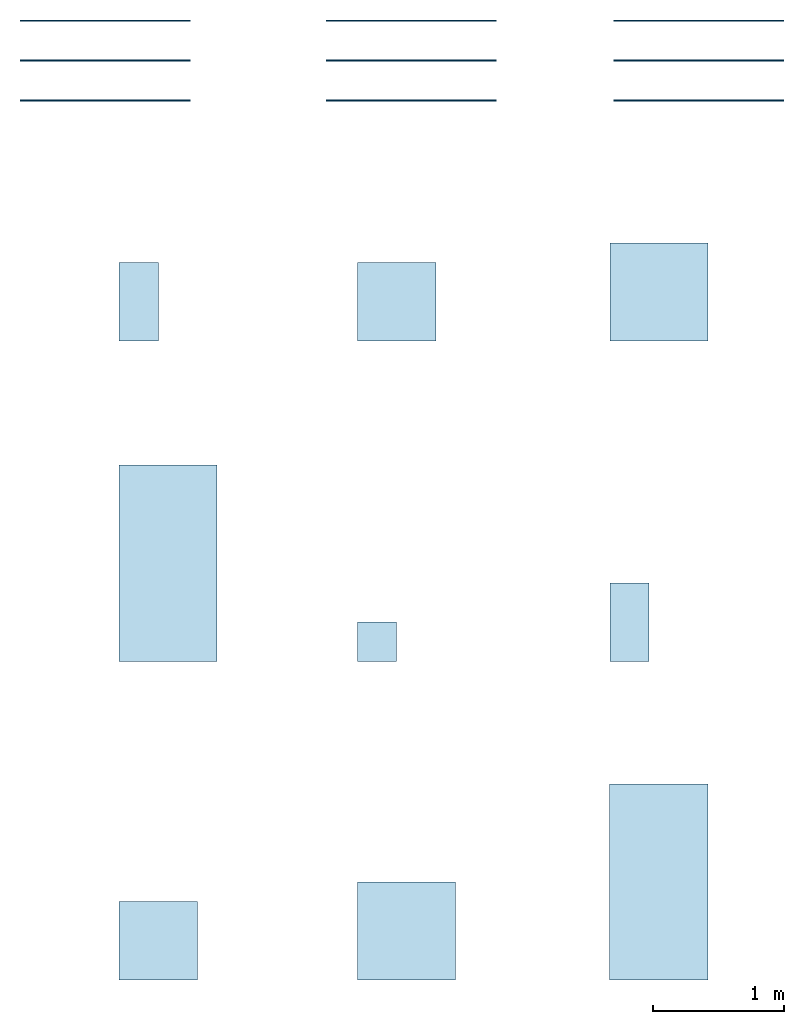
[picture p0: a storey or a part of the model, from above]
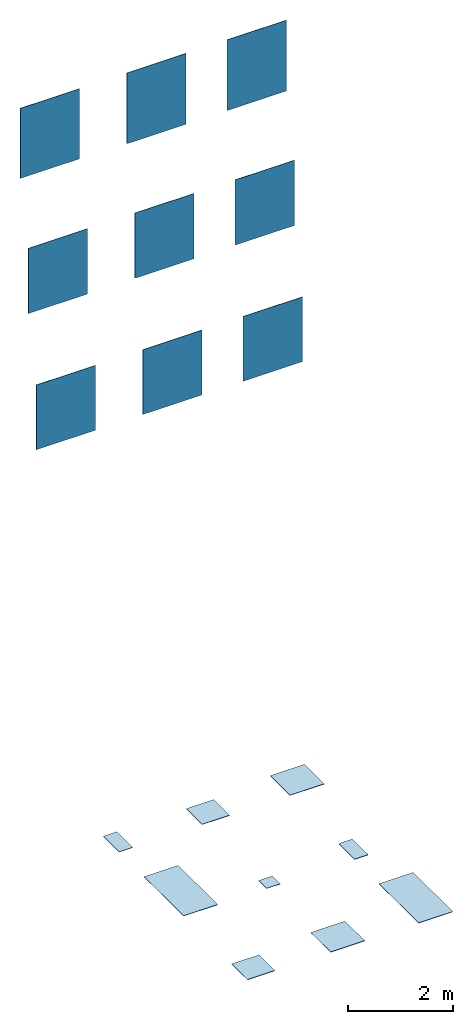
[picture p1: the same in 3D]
Properties of the parts of a building model (IFC2X3)

# File
Description: ViewDefinition [CoordinationView_V2.0]
File name: Project Number
Time: 2021-09-16T11:54:57
Written by: The EXPRESS Data Manager Version 5.02.0100.07 : 28 Aug 2013
Made in: 20190808_0900(x64) - Exporter 19.5.0.0 - Alternate UI 19.5.0.0
Comment: STEP Physical File produced by: The EXPRESS Data Manager Version 5.02.0100.07 : 28 Aug 2013 * Module: EDMstepFileFactory/EDMstandAlone * Creation date: Thu Sep 16 11:54:57 2021 * Host: Davide1988 * Database: C:\Users\DAVIDE~1\AppData\Local\Temp\{4796FC2B-F4B8-4F15-B6A7-0CD5D685FC9C}\ifc * Database version: 5507 * Database creation date: Thu Sep 16 11:54:56 2021 * Schema: IFC2X3 * Model: DataRepository.ifc * Model creation date: Thu Sep 16 11:54:56 2021 * Header model: DataRepository.ifc_HeaderModel * Header model creation date: Thu Sep 16 11:54:56 2021 * EDMuser: sdai-user * EDMgroup: sdai-group * License ID and type: 5605 : Permanent license. Expiry date: * EDMstepFileFactory options: 020000

# IfcProject, Project Number
LongName: Refin-Blended; Phase: Project Status

# IfcSite, Default
RefLatitude: 51, 30, 0, 549316; RefLongitude: 0, -7, -34, -450321; RefElevation: 0 mm
Pset_ProductRequirements - Category: Project Information

# IfcBuilding
Pset_BuildingCommon - NumberOfStoreys: 1
Pset_ProductRequirements - Category: Project Information

# IfcBuildingStorey: Level:Circle Head - Project Datum, Level 0
LongName: Level 0; Elevation: 0 mm
Pset_AirSideSystemInformation - Name: Level 0
Pset_ProductRequirements - Name: Level 0; Category: Levels

# IfcSlab: Floor:Floor_Tiles_Refin-Prestigio_Onyx-Grey-30x30 NZ92, Floor:Floor_Tiles_Refin-Prestigio_Onyx-Grey-30x30 NZ92:304948
In: Level 0
Type - PredefinedType: FLOOR; Material: Prestigio Onyx-Grey-30x30 NZ92 9 mm, <Unnamed> 1 mm
Type - Pset_ConcreteElementGeneral - FireRating: INERT
Type - Pset_ElementShading - Roughness: 914.4 mm; Color: LIGHT-GREY
Type - Pset_FireRatingProperties - SurfaceSpreadOfFlame: INERT
Type - Pset_ManufacturerOccurrence - BarCode: N/A; SerialNumber: N/A
Type - Pset_ManufacturerTypeInformation - ArticleNumber: NZ92; ModelReference: NZ92; ModelLabel: GREY MOSAICO T LUCIDO R 30X30; Manufacturer: info@refin.it; ProductionYear: N/A
Type - Pset_PrecastConcreteElementGeneral - SerialNumber: N/A
Type - Pset_ProductRequirements - Name: Prestigio Onyx_Grey_Mosaico_T_Lucido_30X30 R; Category: Pr_35_93_96_19:Ceramic tiles
Type - Pset_QuantityTakeOff - Reference: N/A
Type - Pset_ReinforcementBarPitchOfSlab - Description: PORCELAIN STONEWARE TILE; Reference: N/A
Type - Pset_SlabCommon - Reference: N/A; IsExternal: no; AcousticRating: N/A; FireRating: INERT; SurfaceSpreadOfFlame: INERT
Type - Pset_Warranty - WarrantyContent: N/A; Exclusions: N/A
Pset_ProductRequirements - Category: Floors
Pset_SlabCommon - LoadBearing: no; PitchAngle: 0 deg

# IfcSlab: Floor:Floor_Tiles_Refin-Prestigio_Onyx-Grey-30x60 NW02, Floor:Floor_Tiles_Refin-Prestigio_Onyx-Grey-30x60 NW02:304668
In: Level 0
Type - PredefinedType: FLOOR; Material: Prestigio Onyx-Grey-30x60 NW02 9 mm, <Unnamed> 1 mm
Type - Pset_ConcreteElementGeneral - FireRating: INERT
Type - Pset_ElementShading - Roughness: 914.4 mm; Color: LIGHT-GREY
Type - Pset_FireRatingProperties - SurfaceSpreadOfFlame: INERT
Type - Pset_ManufacturerOccurrence - BarCode: N/A; SerialNumber: N/A
Type - Pset_ManufacturerTypeInformation - ArticleNumber: NW02; ModelReference: NW02; ModelLabel: GREY LUCIDO R 30X60; Manufacturer: info@refin.it; ProductionYear: N/A
Type - Pset_PrecastConcreteElementGeneral - SerialNumber: N/A
Type - Pset_ProductRequirements - Name: Prestigio Onyx_Grey_Lucido_30X60 R; Category: Pr_35_93_96_19:Ceramic tiles
Type - Pset_QuantityTakeOff - Reference: N/A
Type - Pset_ReinforcementBarPitchOfSlab - Description: PORCELAIN STONEWARE TILE; Reference: N/A
Type - Pset_SlabCommon - Reference: N/A; IsExternal: no; AcousticRating: N/A; FireRating: INERT; SurfaceSpreadOfFlame: INERT
Type - Pset_Warranty - WarrantyContent: N/A; Exclusions: N/A
Pset_ProductRequirements - Category: Floors
Pset_SlabCommon - LoadBearing: no; PitchAngle: 0 deg

# IfcSlab: Floor:Floor_Tiles_Refin-Prestigio_Onyx-Grey-60x60 NZ96, Floor:Floor_Tiles_Refin-Prestigio_Onyx-Grey-60x60 NZ96:324498
In: Level 0
Type - PredefinedType: FLOOR; Material: Prestigio Onyx-Grey-60x60 NZ96 9 mm, <Unnamed> 1 mm
Type - Pset_ConcreteElementGeneral - FireRating: INERT
Type - Pset_ElementShading - Roughness: 914.4 mm; Color: LIGHT-GREY
Type - Pset_FireRatingProperties - SurfaceSpreadOfFlame: INERT
Type - Pset_ManufacturerOccurrence - BarCode: N/A; SerialNumber: N/A
Type - Pset_ManufacturerTypeInformation - ArticleNumber: NZ96; ModelReference: NZ96; ModelLabel: GREY LUCIDO R 60X60; Manufacturer: info@refin.it; ProductionYear: N/A
Type - Pset_PrecastConcreteElementGeneral - SerialNumber: N/A
Type - Pset_ProductRequirements - Name: Prestigio Onyx_Grey_Lucido_60X60 R; Category: Pr_35_93_96_19:Ceramic tiles
Type - Pset_QuantityTakeOff - Reference: N/A
Type - Pset_ReinforcementBarPitchOfSlab - Description: PORCELAIN STONEWARE TILE; Reference: N/A
Type - Pset_SlabCommon - Reference: N/A; IsExternal: no; AcousticRating: N/A; FireRating: INERT; SurfaceSpreadOfFlame: INERT
Type - Pset_Warranty - WarrantyContent: N/A; Exclusions: N/A
Pset_ProductRequirements - Category: Floors
Pset_SlabCommon - LoadBearing: no; PitchAngle: 0 deg

# IfcSlab: Floor:Floor_Tiles_Refin-Prestigio_Onyx-Grey-75x150 NV70, Floor:Floor_Tiles_Refin-Prestigio_Onyx-Grey-75x150 NV70:304956
In: Level 0
Type - PredefinedType: FLOOR; Material: Prestigio Onyx-Grey-75x150 NV70 9 mm, <Unnamed> 1 mm
Type - Pset_ConcreteElementGeneral - FireRating: INERT
Type - Pset_ElementShading - Roughness: 914.4 mm; Color: LIGHT-GREY
Type - Pset_FireRatingProperties - SurfaceSpreadOfFlame: INERT
Type - Pset_ManufacturerOccurrence - BarCode: N/A; SerialNumber: N/A
Type - Pset_ManufacturerTypeInformation - ArticleNumber: NV70; ModelReference: NV70; ModelLabel: GREY LUCIDO R 75X150; Manufacturer: info@refin.it; ProductionYear: N/A
Type - Pset_PrecastConcreteElementGeneral - SerialNumber: N/A
Type - Pset_ProductRequirements - Name: Prestigio Onyx_Grey_Lucido_75X150 R; Category: Pr_35_93_96_19:Ceramic tiles
Type - Pset_QuantityTakeOff - Reference: N/A
Type - Pset_ReinforcementBarPitchOfSlab - Description: PORCELAIN STONEWARE TILE; Reference: N/A
Type - Pset_SlabCommon - Reference: N/A; IsExternal: no; AcousticRating: N/A; FireRating: INERT; SurfaceSpreadOfFlame: INERT
Type - Pset_Warranty - WarrantyContent: N/A; Exclusions: N/A
Pset_ProductRequirements - Category: Floors
Pset_SlabCommon - LoadBearing: no; PitchAngle: 0 deg

# IfcSlab: Floor:Floor_Tiles_Refin-Prestigio_Onyx-Grey-75x75 NZ82, Floor:Floor_Tiles_Refin-Prestigio_Onyx-Grey-75x75 NZ82:285295
In: Level 0
Type - PredefinedType: FLOOR; Material: Prestigio Onyx-Grey-75x75 NZ82 9 mm, <Unnamed> 1 mm
Type - Pset_ConcreteElementGeneral - FireRating: INERT
Type - Pset_ElementShading - Roughness: 914.4 mm; Color: LIGHT-GREY
Type - Pset_FireRatingProperties - SurfaceSpreadOfFlame: INERT
Type - Pset_ManufacturerOccurrence - BarCode: N/A; SerialNumber: N/A
Type - Pset_ManufacturerTypeInformation - ArticleNumber: NZ82; ModelReference: NZ82; ModelLabel: GREY LUCIDO R 75X75; Manufacturer: info@refin.it; ProductionYear: N/A
Type - Pset_PrecastConcreteElementGeneral - SerialNumber: N/A
Type - Pset_ProductRequirements - Name: Prestigio_Onyx_Grey_Lucido_75X75 R; Category: Pr_35_93_96_19:Ceramic tiles
Type - Pset_QuantityTakeOff - Reference: N/A
Type - Pset_ReinforcementBarPitchOfSlab - Description: PORCELAIN STONEWARE TILE; Reference: N/A
Type - Pset_SlabCommon - Reference: N/A; IsExternal: no; AcousticRating: N/A; FireRating: INERT; SurfaceSpreadOfFlame: INERT
Type - Pset_Warranty - WarrantyContent: N/A; Exclusions: N/A
Pset_ProductRequirements - Category: Floors
Pset_SlabCommon - LoadBearing: no; PitchAngle: 0 deg

# IfcSlab: Floor:Floor_Tiles_Refin-Prestigio_Onyx-Grey_Soft-30x60 NW05, Floor:Floor_Tiles_Refin-Prestigio_Onyx-Grey_Soft-30x60 NW05:304932
In: Level 0
Type - PredefinedType: FLOOR; Material: Prestigio Onyx-Grey-Soft-30x60 NW05 9 mm, <Unnamed> 1 mm
Type - Pset_ConcreteElementGeneral - FireRating: INERT
Type - Pset_ElementShading - Roughness: 914.4 mm; Color: LIGHT-GREY
Type - Pset_FireRatingProperties - SurfaceSpreadOfFlame: INERT
Type - Pset_ManufacturerOccurrence - BarCode: N/A; SerialNumber: N/A
Type - Pset_ManufacturerTypeInformation - ArticleNumber: NW05; ModelReference: NW05; ModelLabel: GREY SOFT R 30X60; Manufacturer: info@refin.it; ProductionYear: N/A
Type - Pset_PrecastConcreteElementGeneral - SerialNumber: N/A
Type - Pset_ProductRequirements - Name: Prestigio Onyx_Grey_Soft_30X60 R; Category: Pr_35_93_96_19:Ceramic tiles
Type - Pset_QuantityTakeOff - Reference: N/A
Type - Pset_ReinforcementBarPitchOfSlab - Description: PORCELAIN STONEWARE TILE; Reference: N/A
Type - Pset_SlabCommon - Reference: N/A; IsExternal: no; AcousticRating: N/A; FireRating: INERT; SurfaceSpreadOfFlame: INERT
Type - Pset_Warranty - WarrantyContent: N/A; Exclusions: N/A
Pset_ProductRequirements - Category: Floors
Pset_SlabCommon - LoadBearing: no; PitchAngle: 0 deg

# IfcSlab: Floor:Floor_Tiles_Refin-Prestigio_Onyx-Grey_Soft-60x60 NZ99, Floor:Floor_Tiles_Refin-Prestigio_Onyx-Grey_Soft-60x60 NZ99:305509
In: Level 0
Type - PredefinedType: FLOOR; Material: Prestigio Onyx-Grey-Soft-60x60 NZ99 9 mm, <Unnamed> 1 mm
Type - Pset_ConcreteElementGeneral - FireRating: INERT
Type - Pset_ElementShading - Roughness: 914.4 mm; Color: LIGHT-GREY
Type - Pset_FireRatingProperties - SurfaceSpreadOfFlame: INERT
Type - Pset_ManufacturerOccurrence - BarCode: N/A; SerialNumber: N/A
Type - Pset_ManufacturerTypeInformation - ArticleNumber: NZ99; ModelReference: NZ99; ModelLabel: GREY SOFT R 60X60; Manufacturer: info@refin.it; ProductionYear: N/A
Type - Pset_PrecastConcreteElementGeneral - SerialNumber: N/A
Type - Pset_ProductRequirements - Name: Prestigio Onyx_Grey_Soft_60X60 R; Category: Pr_35_93_96_19:Ceramic tiles
Type - Pset_QuantityTakeOff - Reference: N/A
Type - Pset_ReinforcementBarPitchOfSlab - Description: PORCELAIN STONEWARE TILE; Reference: N/A
Type - Pset_SlabCommon - Reference: N/A; IsExternal: no; AcousticRating: N/A; FireRating: INERT; SurfaceSpreadOfFlame: INERT
Type - Pset_Warranty - WarrantyContent: N/A; Exclusions: N/A
Pset_ProductRequirements - Category: Floors
Pset_SlabCommon - LoadBearing: no; PitchAngle: 0 deg

# IfcSlab: Floor:Floor_Tiles_Refin-Prestigio_Onyx-Grey_Soft-75x150 NZ79, Floor:Floor_Tiles_Refin-Prestigio_Onyx-Grey_Soft-75x150 NZ79:339650
In: Level 0
Type - PredefinedType: FLOOR; Material: Prestigio Onyx-Grey-Soft-75x150 NZ79 9 mm, <Unnamed> 1 mm
Type - Pset_ConcreteElementGeneral - FireRating: INERT
Type - Pset_ElementShading - Roughness: 914.4 mm; Color: LIGHT-GREY
Type - Pset_FireRatingProperties - SurfaceSpreadOfFlame: INERT
Type - Pset_ManufacturerOccurrence - BarCode: N/A; SerialNumber: N/A
Type - Pset_ManufacturerTypeInformation - ArticleNumber: NZ79; ModelReference: NZ79; ModelLabel: GREY SOFT R 75X150; Manufacturer: info@refin.it; ProductionYear: N/A
Type - Pset_PrecastConcreteElementGeneral - SerialNumber: N/A
Type - Pset_ProductRequirements - Name: Prestigio Onyx_Grey_Soft_75X150 R; Category: Pr_35_93_96_19:Ceramic tiles
Type - Pset_QuantityTakeOff - Reference: N/A
Type - Pset_ReinforcementBarPitchOfSlab - Description: PORCELAIN STONEWARE TILE; Reference: N/A
Type - Pset_SlabCommon - Reference: N/A; IsExternal: no; AcousticRating: N/A; FireRating: INERT; SurfaceSpreadOfFlame: INERT
Type - Pset_Warranty - WarrantyContent: N/A; Exclusions: N/A
Pset_ProductRequirements - Category: Floors
Pset_SlabCommon - LoadBearing: no; PitchAngle: 0 deg

# IfcSlab: Floor:Floor_Tiles_Refin-Prestigio_Onyx-Grey_Soft-75x75 NZ85, Floor:Floor_Tiles_Refin-Prestigio_Onyx-Grey_Soft-75x75 NZ85:339635
In: Level 0
Type - PredefinedType: FLOOR; Material: Prestigio Onyx-Grey-Soft-75x75 NZ85 9 mm, <Unnamed> 1 mm
Type - Pset_ConcreteElementGeneral - FireRating: INERT
Type - Pset_ElementShading - Roughness: 914.4 mm; Color: LIGHT-GREY
Type - Pset_FireRatingProperties - SurfaceSpreadOfFlame: INERT
Type - Pset_ManufacturerOccurrence - BarCode: N/A; SerialNumber: N/A
Type - Pset_ManufacturerTypeInformation - ArticleNumber: NZ85; ModelReference: NZ85; ModelLabel: GREY SOFT R 75X75; Manufacturer: info@refin.it; ProductionYear: N/A
Type - Pset_PrecastConcreteElementGeneral - SerialNumber: N/A
Type - Pset_ProductRequirements - Name: Prestigio Onyx_Grey_Soft_75X75 R; Category: Pr_35_93_96_19:Ceramic tiles
Type - Pset_QuantityTakeOff - Reference: N/A
Type - Pset_ReinforcementBarPitchOfSlab - Description: PORCELAIN STONEWARE TILE; Reference: N/A
Type - Pset_SlabCommon - Reference: N/A; IsExternal: no; AcousticRating: N/A; FireRating: INERT; SurfaceSpreadOfFlame: INERT
Type - Pset_Warranty - WarrantyContent: N/A; Exclusions: N/A
Pset_ProductRequirements - Category: Floors
Pset_SlabCommon - LoadBearing: no; PitchAngle: 0 deg

# IfcWallStandardCase: Basic Wall:Wall_Tiles_Refin-Prestigio_Onyx-Grey-30x30 NZ92, Basic Wall:Wall_Tiles_Refin-Prestigio_Onyx-Grey-30x30 NZ92:335490
In: Level 0
Type - PredefinedType: STANDARD; Material: <Unnamed> 1 mm, Prestigio Onyx-Grey-30x30 NZ92 9 mm
Type - Pset_ConcreteElementGeneral - FireRating: INERT
Type - Pset_ElementShading - Roughness: 914.4 mm; Color: LIGHT-GREY
Type - Pset_FireRatingProperties - SurfaceSpreadOfFlame: INERT
Type - Pset_ManufacturerOccurrence - BarCode: N/A; SerialNumber: N/A
Type - Pset_ManufacturerTypeInformation - ArticleNumber: NZ92; ModelReference: NZ92; ModelLabel: GREY MOSAICO T LUCIDO R 30X30; Manufacturer: info@refin.it; ProductionYear: N/A
Type - Pset_PrecastConcreteElementGeneral - SerialNumber: N/A
Type - Pset_ProductRequirements - Name: Prestigio Onyx_Grey_Mosaico_T_Lucido_30X30 R; Category: Pr_35_93_96_19:Ceramic tiles
Type - Pset_QuantityTakeOff - Reference: N/A
Type - Pset_ReinforcementBarPitchOfWall - Description: PORCELAIN STONEWARE TILE; Reference: N/A
Type - Pset_WallCommon - Reference: N/A; IsExternal: no; AcousticRating: N/A; FireRating: INERT; SurfaceSpreadOfFlame: INERT
Type - Pset_Warranty - WarrantyContent: N/A; Exclusions: N/A
Pset_ProductRequirements - Category: Walls
Pset_WallCommon - LoadBearing: no; ExtendToStructure: no

# IfcWallStandardCase: Basic Wall:Wall_Tiles_Refin-Prestigio_Onyx-Grey-30x60 NW02, Basic Wall:Wall_Tiles_Refin-Prestigio_Onyx-Grey-30x60 NW02:334895
In: Level 0
Type - PredefinedType: STANDARD; Material: <Unnamed> 1 mm, Prestigio Onyx-Grey-30x60 NW02 9 mm
Type - Pset_ConcreteElementGeneral - FireRating: INERT
Type - Pset_ElementShading - Roughness: 914.4 mm; Color: LIGHT-GREY
Type - Pset_FireRatingProperties - SurfaceSpreadOfFlame: INERT
Type - Pset_ManufacturerOccurrence - BarCode: N/A; SerialNumber: N/A
Type - Pset_ManufacturerTypeInformation - ArticleNumber: NW02; ModelReference: NW02; ModelLabel: GREY LUCIDO R 30X60; Manufacturer: info@refin.it; ProductionYear: N/A
Type - Pset_PrecastConcreteElementGeneral - SerialNumber: N/A
Type - Pset_ProductRequirements - Name: Prestigio Onyx_Grey_Lucido_30X60 R; Category: Pr_35_93_96_19:Ceramic tiles
Type - Pset_QuantityTakeOff - Reference: N/A
Type - Pset_ReinforcementBarPitchOfWall - Description: PORCELAIN STONEWARE TILE; Reference: N/A
Type - Pset_WallCommon - Reference: N/A; IsExternal: no; AcousticRating: N/A; FireRating: INERT; SurfaceSpreadOfFlame: INERT
Type - Pset_Warranty - WarrantyContent: N/A; Exclusions: N/A
Pset_ProductRequirements - Category: Walls
Pset_WallCommon - LoadBearing: no; ExtendToStructure: no

# IfcWallStandardCase: Basic Wall:Wall_Tiles_Refin-Prestigio_Onyx-Grey-60x60 NZ96, Basic Wall:Wall_Tiles_Refin-Prestigio_Onyx-Grey-60x60 NZ96:333696
In: Level 0
Type - PredefinedType: STANDARD; Material: <Unnamed> 1 mm, Prestigio Onyx-Grey-60x60 NZ96 9 mm
Type - Pset_ConcreteElementGeneral - FireRating: INERT
Type - Pset_ElementShading - Roughness: 914.4 mm; Color: LIGHT-GREY
Type - Pset_FireRatingProperties - SurfaceSpreadOfFlame: INERT
Type - Pset_ManufacturerOccurrence - BarCode: N/A; SerialNumber: N/A
Type - Pset_ManufacturerTypeInformation - ArticleNumber: NZ96; ModelReference: NZ96; ModelLabel: GREY LUCIDO R 60X60; Manufacturer: info@refin.it; ProductionYear: N/A
Type - Pset_PrecastConcreteElementGeneral - SerialNumber: N/A
Type - Pset_ProductRequirements - Name: Prestigio Onyx_Grey_Lucido_60X60 R; Category: Pr_35_93_96_19:Ceramic tiles
Type - Pset_QuantityTakeOff - Reference: N/A
Type - Pset_ReinforcementBarPitchOfWall - Description: PORCELAIN STONEWARE TILE; Reference: N/A
Type - Pset_WallCommon - Reference: N/A; IsExternal: no; AcousticRating: N/A; FireRating: INERT; SurfaceSpreadOfFlame: INERT
Type - Pset_Warranty - WarrantyContent: N/A; Exclusions: N/A
Pset_ProductRequirements - Category: Walls
Pset_WallCommon - LoadBearing: no; ExtendToStructure: no

# IfcWallStandardCase: Basic Wall:Wall_Tiles_Refin-Prestigio_Onyx-Grey-75x150 NV70, Basic Wall:Wall_Tiles_Refin-Prestigio_Onyx-Grey-75x150 NV70:335038
In: Level 0
Type - PredefinedType: STANDARD; Material: <Unnamed> 1 mm, Prestigio Onyx-Grey-75x150 NV70 9 mm
Type - Pset_ConcreteElementGeneral - FireRating: INERT
Type - Pset_ElementShading - Roughness: 914.4 mm; Color: LIGHT-GREY
Type - Pset_FireRatingProperties - SurfaceSpreadOfFlame: INERT
Type - Pset_ManufacturerOccurrence - BarCode: N/A; SerialNumber: N/A
Type - Pset_ManufacturerTypeInformation - ArticleNumber: NV70; ModelReference: NV70; ModelLabel: GREY LUCIDO R 75X150; Manufacturer: info@refin.it; ProductionYear: N/A
Type - Pset_PrecastConcreteElementGeneral - SerialNumber: N/A
Type - Pset_ProductRequirements - Name: Prestigio Onyx_Grey_Lucido_75X150 R; Category: Pr_35_93_96_19:Ceramic tiles
Type - Pset_QuantityTakeOff - Reference: N/A
Type - Pset_ReinforcementBarPitchOfWall - Description: PORCELAIN STONEWARE TILE; Reference: N/A
Type - Pset_WallCommon - Reference: N/A; IsExternal: no; AcousticRating: N/A; FireRating: INERT; SurfaceSpreadOfFlame: INERT
Type - Pset_Warranty - WarrantyContent: N/A; Exclusions: N/A
Pset_ProductRequirements - Category: Walls
Pset_WallCommon - LoadBearing: no; ExtendToStructure: no

# IfcWallStandardCase: Basic Wall:Wall_Tiles_Refin-Prestigio_Onyx-Grey-75x75 NZ82, Basic Wall:Wall_Tiles_Refin-Prestigio_Onyx-Grey-75x75 NZ82:334553
In: Level 0
Type - PredefinedType: STANDARD; Material: <Unnamed> 1 mm, Prestigio Onyx-Grey-75x75 NZ82 9 mm
Type - Pset_ConcreteElementGeneral - FireRating: INERT
Type - Pset_ElementShading - Roughness: 914.4 mm; Color: LIGHT-GREY
Type - Pset_FireRatingProperties - SurfaceSpreadOfFlame: INERT
Type - Pset_ManufacturerOccurrence - BarCode: N/A; SerialNumber: N/A
Type - Pset_ManufacturerTypeInformation - ArticleNumber: NZ82; ModelReference: NZ82; ModelLabel: GREY LUCIDO R 75X75; Manufacturer: info@refin.it; ProductionYear: N/A
Type - Pset_PrecastConcreteElementGeneral - SerialNumber: N/A
Type - Pset_ProductRequirements - Name: Prestigio_Onyx_Grey_Lucido_75X75 R; Category: Pr_35_93_96_19:Ceramic tiles
Type - Pset_QuantityTakeOff - Reference: N/A
Type - Pset_ReinforcementBarPitchOfWall - Description: PORCELAIN STONEWARE TILE; Reference: N/A
Type - Pset_WallCommon - Reference: N/A; IsExternal: no; AcousticRating: N/A; FireRating: INERT; SurfaceSpreadOfFlame: INERT
Type - Pset_Warranty - WarrantyContent: N/A; Exclusions: N/A
Pset_ProductRequirements - Category: Walls
Pset_WallCommon - LoadBearing: no; ExtendToStructure: no

# IfcWallStandardCase: Basic Wall:Wall_Tiles_Refin-Prestigio_Onyx-Grey_Soft_30x60 NW05, Basic Wall:Wall_Tiles_Refin-Prestigio_Onyx-Grey_Soft_30x60 NW05:335882
In: Level 0
Type - PredefinedType: STANDARD; Material: <Unnamed> 1 mm, Prestigio Onyx-Grey-Soft-30x60 NW05 9 mm
Type - Pset_ConcreteElementGeneral - FireRating: INERT
Type - Pset_ElementShading - Roughness: 914.4 mm; Color: LIGHT-GREY
Type - Pset_FireRatingProperties - SurfaceSpreadOfFlame: INERT
Type - Pset_ManufacturerOccurrence - BarCode: N/A; SerialNumber: N/A
Type - Pset_ManufacturerTypeInformation - ArticleNumber: NW05; ModelReference: NW05; ModelLabel: GREY SOFT R 30X60; Manufacturer: info@refin.it; ProductionYear: N/A
Type - Pset_PrecastConcreteElementGeneral - SerialNumber: N/A
Type - Pset_ProductRequirements - Name: Prestigio_Onyx_Grey_Soft_30X60 R; Category: Pr_35_93_96_19:Ceramic tiles
Type - Pset_QuantityTakeOff - Reference: N/A
Type - Pset_ReinforcementBarPitchOfWall - Description: PORCELAIN STONEWARE TILE; Reference: N/A
Type - Pset_WallCommon - Reference: N/A; IsExternal: no; AcousticRating: N/A; FireRating: INERT; SurfaceSpreadOfFlame: INERT
Type - Pset_Warranty - WarrantyContent: N/A; Exclusions: N/A
Pset_ProductRequirements - Category: Walls
Pset_WallCommon - LoadBearing: no; ExtendToStructure: no

# IfcWallStandardCase: Basic Wall:Wall_Tiles_Refin-Prestigio_Onyx-Grey_Soft_60x60 NZ99, Basic Wall:Wall_Tiles_Refin-Prestigio_Onyx-Grey_Soft_60x60 NZ99:336183
In: Level 0
Type - PredefinedType: STANDARD; Material: <Unnamed> 1 mm, Prestigio Onyx-Grey-Soft-60x60 NZ99 9 mm
Type - Pset_ConcreteElementGeneral - FireRating: INERT
Type - Pset_ElementShading - Roughness: 914.4 mm; Color: LIGHT-GREY
Type - Pset_FireRatingProperties - SurfaceSpreadOfFlame: INERT
Type - Pset_ManufacturerOccurrence - BarCode: N/A; SerialNumber: N/A
Type - Pset_ManufacturerTypeInformation - ArticleNumber: NZ99; ModelReference: NZ99; ModelLabel: GREY SOFT R 60X60; Manufacturer: info@refin.it; ProductionYear: N/A
Type - Pset_PrecastConcreteElementGeneral - SerialNumber: N/A
Type - Pset_ProductRequirements - Name: Prestigio_Onyx_Grey_Soft_60X60 R; Category: Pr_35_93_96_19:Ceramic tiles
Type - Pset_QuantityTakeOff - Reference: N/A
Type - Pset_ReinforcementBarPitchOfWall - Description: PORCELAIN STONEWARE TILE; Reference: N/A
Type - Pset_WallCommon - Reference: N/A; IsExternal: no; AcousticRating: N/A; FireRating: INERT; SurfaceSpreadOfFlame: INERT
Type - Pset_Warranty - WarrantyContent: N/A; Exclusions: N/A
Pset_ProductRequirements - Category: Walls
Pset_WallCommon - LoadBearing: no; ExtendToStructure: no

# IfcWallStandardCase: Basic Wall:Wall_Tiles_Refin-Prestigio_Onyx-Grey_Soft_75x150 NZ79, Basic Wall:Wall_Tiles_Refin-Prestigio_Onyx-Grey_Soft_75x150 NZ79:339723
In: Level 0
Type - PredefinedType: STANDARD; Material: <Unnamed> 1 mm, Prestigio Onyx-Grey-Soft-75x150 NZ79 9 mm
Type - Pset_ConcreteElementGeneral - FireRating: INERT
Type - Pset_ElementShading - Roughness: 914.4 mm; Color: LIGHT-GREY
Type - Pset_FireRatingProperties - SurfaceSpreadOfFlame: INERT
Type - Pset_ManufacturerOccurrence - BarCode: N/A; SerialNumber: N/A
Type - Pset_ManufacturerTypeInformation - ArticleNumber: NZ79; ModelReference: NZ79; ModelLabel: GREY SOFT R 75X150; Manufacturer: info@refin.it; ProductionYear: N/A
Type - Pset_PrecastConcreteElementGeneral - SerialNumber: N/A
Type - Pset_ProductRequirements - Name: Prestigio_Onyx_Grey_Soft_75X150 R; Category: Pr_35_93_96_19:Ceramic tiles
Type - Pset_QuantityTakeOff - Reference: N/A
Type - Pset_ReinforcementBarPitchOfWall - Description: PORCELAIN STONEWARE TILE; Reference: N/A
Type - Pset_WallCommon - Reference: N/A; IsExternal: no; AcousticRating: N/A; FireRating: INERT; SurfaceSpreadOfFlame: INERT
Type - Pset_Warranty - WarrantyContent: N/A; Exclusions: N/A
Pset_ProductRequirements - Category: Walls
Pset_WallCommon - LoadBearing: no; ExtendToStructure: no

# IfcWallStandardCase: Basic Wall:Wall_Tiles_Refin-Prestigio_Onyx-Grey_Soft_75x75 NZ85, Basic Wall:Wall_Tiles_Refin-Prestigio_Onyx-Grey_Soft_75x75 NZ85:339715
In: Level 0
Type - PredefinedType: STANDARD; Material: <Unnamed> 1 mm, Prestigio Onyx-Grey-Soft-75x75 NZ85 9 mm
Type - Pset_ConcreteElementGeneral - FireRating: INERT
Type - Pset_ElementShading - Roughness: 914.4 mm; Color: LIGHT-GREY
Type - Pset_FireRatingProperties - SurfaceSpreadOfFlame: INERT
Type - Pset_ManufacturerOccurrence - BarCode: N/A; SerialNumber: N/A
Type - Pset_ManufacturerTypeInformation - ArticleNumber: NZ85; ModelReference: NZ85; ModelLabel: GREY SOFT R 75X75; Manufacturer: info@refin.it; ProductionYear: N/A
Type - Pset_PrecastConcreteElementGeneral - SerialNumber: N/A
Type - Pset_ProductRequirements - Name: Prestigio_Onyx_Grey_Soft_75X75 R; Category: Pr_35_93_96_19:Ceramic tiles
Type - Pset_QuantityTakeOff - Reference: N/A
Type - Pset_ReinforcementBarPitchOfWall - Description: PORCELAIN STONEWARE TILE; Reference: N/A
Type - Pset_WallCommon - Reference: N/A; IsExternal: no; AcousticRating: N/A; FireRating: INERT; SurfaceSpreadOfFlame: INERT
Type - Pset_Warranty - WarrantyContent: N/A; Exclusions: N/A
Pset_ProductRequirements - Category: Walls
Pset_WallCommon - LoadBearing: no; ExtendToStructure: no
